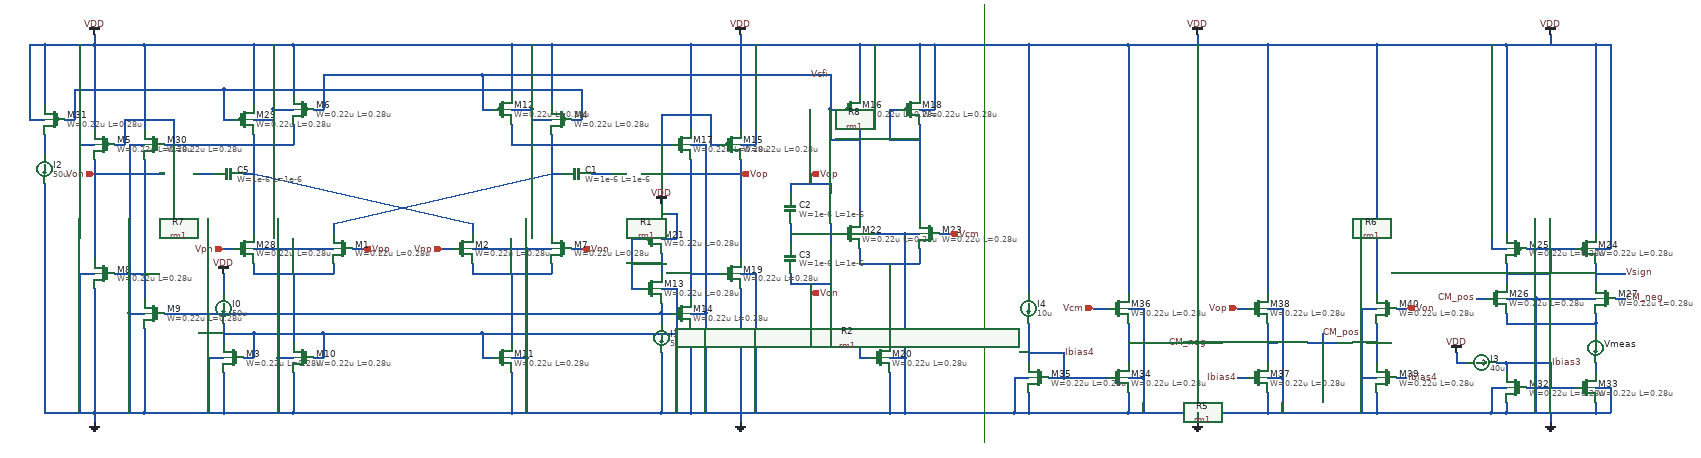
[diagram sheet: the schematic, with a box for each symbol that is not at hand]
v {xschem version=3.4.8RC file_version=1.3}
G {}
K {}
V {}
S {}
F {}
E {}
L 4 2250 -900 2250 -20 {}
N 780 -640 780 -440 {lab=#net1}
N 940 -380 940 -360 {lab=#net2}
N 780 -360 940 -360 {lab=#net2}
N 780 -380 780 -360 {lab=#net2}
N 1380 -640 1380 -440 {lab=#net3}
N 1220 -380 1220 -360 {lab=#net4}
N 1220 -360 1380 -360 {lab=#net4}
N 1380 -380 1380 -360 {lab=#net4}
N 360 -640 360 -600 {lab=#net5}
N 360 -820 360 -700 {lab=VDD}
N 360 -820 460 -820 {lab=VDD}
N 460 -820 560 -820 {lab=VDD}
N 360 -540 360 -80 {lab=GND}
N 460 -330 460 -80 {lab=GND}
N 360 -80 460 -80 {lab=GND}
N 560 -250 560 -80 {lab=GND}
N 460 -80 560 -80 {lab=GND}
N 720 -670 740 -670 {lab=#net6}
N 500 -360 560 -360 {lab=#net7}
N 560 -80 720 -80 {lab=GND}
N 720 -80 860 -80 {lab=GND}
N 860 -80 1300 -80 {lab=GND}
N 780 -820 780 -700 {lab=VDD}
N 560 -820 780 -820 {lab=VDD}
N 940 -460 940 -440 {lab=#net3}
N 1220 -460 1220 -440 {lab=#net1}
N 460 -590 460 -390 {lab=Von}
N 560 -590 560 -310 {lab=#net7}
N 460 -820 460 -650 {lab=VDD}
N 560 -820 560 -650 {lab=VDD}
N 600 -620 780 -620 {lab=#net1}
N 620 -670 620 -620 {lab=#net1}
N 520 -670 620 -670 {lab=#net1}
N 520 -670 520 -620 {lab=#net1}
N 500 -620 520 -620 {lab=#net1}
N 780 -620 860 -620 {lab=#net1}
N 860 -660 860 -620 {lab=#net1}
N 860 -820 860 -720 {lab=VDD}
N 780 -820 860 -820 {lab=VDD}
N 900 -690 920 -690 {lab=Vcfi}
N 1240 -690 1260 -690 {lab=Vcfi}
N 1300 -660 1300 -620 {lab=#net3}
N 1300 -620 1380 -620 {lab=#net3}
N 860 -820 1300 -820 {lab=VDD}
N 1300 -820 1300 -720 {lab=VDD}
N 1300 -820 1380 -820 {lab=VDD}
N 1380 -820 1380 -700 {lab=VDD}
N 1700 -620 1720 -620 {lab=#net3}
N 1700 -680 1700 -620 {lab=#net3}
N 1600 -680 1700 -680 {lab=#net3}
N 1600 -680 1600 -620 {lab=#net3}
N 1660 -820 1660 -650 {lab=VDD}
N 1760 -820 1760 -650 {lab=VDD}
N 1660 -820 1760 -820 {lab=VDD}
N 1660 -590 1660 -310 {lab=#net8}
N 1660 -250 1660 -80 {lab=GND}
N 1660 -360 1720 -360 {lab=#net8}
N 1760 -590 1760 -390 {lab=Vop}
N 1760 -330 1760 -80 {lab=GND}
N 1660 -80 1760 -80 {lab=GND}
N 1540 -330 1560 -330 {lab=#net9}
N 1540 -430 1540 -330 {lab=#net9}
N 1540 -430 1560 -430 {lab=#net9}
N 1600 -400 1600 -360 {lab=#net9}
N 1540 -380 1600 -380 {lab=#net9}
N 1600 -280 1600 -260 {lab=#net10}
N 1600 -300 1600 -280 {lab=#net10}
N 1600 -200 1600 -80 {lab=GND}
N 1300 -80 1600 -80 {lab=GND}
N 1600 -80 1660 -80 {lab=GND}
N 600 -280 1600 -280 {lab=#net10}
N 1600 -280 1620 -280 {lab=#net10}
N 1380 -620 1620 -620 {lab=#net3}
N 1380 -820 1660 -820 {lab=VDD}
N 1420 -410 1440 -410 {lab=Vnn}
N 1160 -410 1180 -410 {lab=Vnp}
N 980 -410 1000 -410 {lab=Vpp}
N 720 -410 740 -410 {lab=Vpn}
N 1940 -690 1960 -690 {lab=Vcfi}
N 1940 -690 1940 -630 {lab=Vcfi}
N 1940 -630 2000 -630 {lab=Vcfi}
N 2060 -690 2080 -690 {lab=#net11}
N 2060 -690 2060 -630 {lab=#net11}
N 2060 -630 2120 -630 {lab=#net11}
N 940 -460 1380 -560 {lab=#net3}
N 780 -560 1220 -460 {lab=#net1}
N 2000 -660 2000 -470 {lab=Vcfi}
N 2120 -660 2120 -470 {lab=#net11}
N 1940 -460 1940 -420 {lab=#net12}
N 1860 -460 1860 -420 {lab=#net12}
N 1860 -540 1860 -520 {lab=Vop}
N 1860 -540 1940 -540 {lab=Vop}
N 1940 -540 1940 -520 {lab=Vop}
N 1940 -360 1940 -340 {lab=Von}
N 1860 -340 1940 -340 {lab=Von}
N 1860 -360 1860 -340 {lab=Von}
N 1940 -440 1960 -440 {lab=#net12}
N 1860 -440 1940 -440 {lab=#net12}
N 1760 -820 2000 -820 {lab=VDD}
N 2000 -820 2000 -720 {lab=VDD}
N 2000 -820 2120 -820 {lab=VDD}
N 2120 -820 2120 -720 {lab=VDD}
N 2120 -410 2120 -380 {lab=#net13}
N 2000 -380 2120 -380 {lab=#net13}
N 2000 -410 2000 -380 {lab=#net13}
N 1760 -80 2060 -80 {lab=GND}
N 2160 -440 2180 -440 {lab=Vcm}
N 1900 -560 1900 -540 {lab=Vop}
N 1900 -340 1900 -320 {lab=Von}
N 720 -160 720 -80 {lab=GND}
N 1300 -160 1300 -80 {lab=GND}
N 2060 -160 2060 -80 {lab=GND}
N 2060 -380 2060 -220 {lab=#net13}
N 860 -360 860 -220 {lab=#net2}
N 1300 -360 1300 -220 {lab=#net4}
N 720 -240 780 -240 {lab=#net14}
N 780 -240 780 -190 {lab=#net14}
N 760 -190 780 -190 {lab=#net14}
N 900 -190 920 -190 {lab=#net14}
N 920 -240 920 -190 {lab=#net14}
N 780 -240 920 -240 {lab=#net14}
N 920 -240 1240 -240 {lab=#net14}
N 1240 -240 1240 -190 {lab=#net14}
N 1240 -190 1260 -190 {lab=#net14}
N 1240 -240 2000 -240 {lab=#net14}
N 2000 -240 2000 -190 {lab=#net14}
N 2000 -190 2020 -190 {lab=#net14}
N 400 -670 420 -670 {lab=#net6}
N 860 -160 860 -80 {lab=GND}
N 1420 -670 1440 -670 {lab=#net6}
N 820 -690 860 -690 {lab=VDD}
N 820 -690 820 -670 {lab=VDD}
N 780 -670 820 -670 {lab=VDD}
N 1300 -690 1340 -690 {lab=VDD}
N 1340 -690 1340 -670 {lab=VDD}
N 1340 -670 1380 -670 {lab=VDD}
N 2120 -690 2150 -690 {lab=VDD}
N 2000 -690 2030 -690 {lab=VDD}
N 1760 -620 1790 -620 {lab=VDD}
N 2060 -190 2090 -190 {lab=GND}
N 1660 -280 1690 -280 {lab=GND}
N 1600 -330 1630 -330 {lab=GND}
N 1760 -360 1790 -360 {lab=GND}
N 1660 -620 1690 -620 {lab=GND}
N 690 -190 720 -190 {lab=GND}
N 830 -190 860 -190 {lab=GND}
N 530 -280 560 -280 {lab=GND}
N 430 -360 460 -360 {lab=GND}
N 530 -620 560 -620 {lab=GND}
N 3340 -410 3440 -410 {lab=#net15}
N 3520 -310 3540 -310 {lab=CM_neg}
N 3240 -310 3260 -310 {lab=CM_pos}
N 3390 -410 3390 -360 {lab=#net15}
N 3300 -360 3390 -360 {lab=#net15}
N 3300 -280 3300 -260 {lab=#net16}
N 3300 -260 3480 -260 {lab=#net16}
N 3480 -280 3480 -260 {lab=#net16}
N 3340 -130 3440 -130 {lab=Ibias3}
N 3390 -180 3390 -130 {lab=Ibias3}
N 3300 -180 3390 -180 {lab=Ibias3}
N 3480 -100 3480 -80 {lab=GND}
N 3300 -80 3480 -80 {lab=GND}
N 3300 -100 3300 -80 {lab=GND}
N 3080 -290 3100 -290 {lab=Von}
N 2760 -290 2780 -290 {lab=Vop}
N 3480 -360 3540 -360 {lab=Vsign}
N 3040 -260 3040 -180 {lab=#net17}
N 2820 -260 2820 -180 {lab=#net18}
N 2820 -120 2820 -80 {lab=GND}
N 2820 -80 3040 -80 {lab=GND}
N 3040 -120 3040 -80 {lab=GND}
N 3010 -150 3040 -150 {lab=GND}
N 3010 -150 3010 -80 {lab=GND}
N 2850 -150 2850 -80 {lab=GND}
N 2820 -150 2850 -150 {lab=GND}
N 2380 -150 2410 -150 {lab=Ibias4}
N 2410 -200 2410 -150 {lab=Ibias4}
N 2340 -200 2410 -200 {lab=Ibias4}
N 2410 -150 2500 -150 {lab=Ibias4}
N 2540 -260 2540 -180 {lab=CM_neg}
N 2540 -80 2820 -80 {lab=GND}
N 2540 -120 2540 -80 {lab=GND}
N 2340 -80 2540 -80 {lab=GND}
N 2340 -120 2340 -80 {lab=GND}
N 2310 -150 2340 -150 {lab=GND}
N 2310 -150 2310 -80 {lab=GND}
N 2310 -80 2340 -80 {lab=GND}
N 2540 -150 2570 -150 {lab=GND}
N 2570 -150 2570 -80 {lab=GND}
N 2540 -290 2570 -290 {lab=GND}
N 2570 -290 2570 -150 {lab=GND}
N 2820 -290 2850 -290 {lab=GND}
N 2850 -290 2850 -150 {lab=GND}
N 3010 -290 3040 -290 {lab=GND}
N 3010 -290 3010 -150 {lab=GND}
N 2470 -290 2500 -290 {lab=Vcm}
N 2540 -220 2620 -220 {lab=CM_neg}
N 2900 -220 2960 -220 {lab=CM_pos}
N 2820 -220 2840 -220 {lab=#net18}
N 3020 -220 3040 -220 {lab=#net17}
N 2930 -240 2930 -220 {lab=CM_pos}
N 2760 -150 2780 -150 {lab=Ibias4}
N 3080 -150 3100 -150 {lab=Ibias4}
N 1940 -760 1940 -690 {lab=Vcfi}
N 1240 -760 1940 -760 {lab=Vcfi}
N 1240 -760 1240 -690 {lab=Vcfi}
N 920 -760 1240 -760 {lab=Vcfi}
N 920 -760 920 -690 {lab=Vcfi}
N 1440 -730 1440 -670 {lab=#net6}
N 720 -730 1440 -730 {lab=#net6}
N 720 -730 720 -670 {lab=#net6}
N 420 -730 720 -730 {lab=#net6}
N 420 -730 420 -670 {lab=#net6}
N 820 -820 820 -690 {lab=VDD}
N 1340 -820 1340 -690 {lab=VDD}
N 3300 -380 3300 -340 {lab=#net15}
N 3480 -380 3480 -340 {lab=Vsign}
N 3280 -180 3300 -180 {lab=Ibias3}
N 3200 -180 3220 -180 {lab=VDD}
N 3200 -200 3200 -180 {lab=VDD}
N 3300 -180 3300 -160 {lab=Ibias3}
N 3480 -180 3480 -160 {lab=#net19}
N 3480 -260 3480 -240 {lab=#net16}
N 3270 -410 3300 -410 {lab=VDD}
N 3480 -410 3510 -410 {lab=VDD}
N 3480 -130 3510 -130 {lab=GND}
N 3510 -130 3510 -80 {lab=GND}
N 3480 -80 3510 -80 {lab=GND}
N 3270 -80 3300 -80 {lab=GND}
N 3270 -130 3270 -80 {lab=GND}
N 3270 -130 3300 -130 {lab=GND}
N 2090 -190 2090 -80 {lab=GND}
N 2060 -80 2090 -80 {lab=GND}
N 1690 -280 1690 -80 {lab=GND}
N 1300 -190 1330 -190 {lab=GND}
N 1330 -190 1330 -80 {lab=GND}
N 830 -190 830 -80 {lab=GND}
N 690 -190 690 -80 {lab=GND}
N 530 -280 530 -80 {lab=GND}
N 430 -360 430 -80 {lab=GND}
N 760 -560 780 -560 {lab=#net1}
N 660 -560 700 -560 {lab=#net20}
N 460 -560 600 -560 {lab=Von}
N 1380 -560 1400 -560 {lab=#net3}
N 1460 -560 1500 -560 {lab=#net21}
N 1560 -560 1760 -560 {lab=Vop}
N 2150 -820 2150 -690 {lab=VDD}
N 2120 -820 2150 -820 {lab=VDD}
N 2030 -820 2030 -690 {lab=VDD}
N 1790 -820 1790 -620 {lab=VDD}
N 430 -620 460 -620 {lab=VDD}
N 430 -820 430 -620 {lab=VDD}
N 330 -670 360 -670 {lab=VDD}
N 330 -820 330 -670 {lab=VDD}
N 330 -820 360 -820 {lab=VDD}
N 2090 -440 2090 -190 {lab=GND}
N 2090 -440 2120 -440 {lab=GND}
N 2000 -440 2090 -440 {lab=GND}
N 1690 -620 1690 -280 {lab=GND}
N 1790 -360 1790 -80 {lab=GND}
N 1330 -410 1330 -190 {lab=GND}
N 1330 -410 1380 -410 {lab=GND}
N 1220 -410 1330 -410 {lab=GND}
N 830 -410 830 -190 {lab=GND}
N 780 -410 830 -410 {lab=GND}
N 830 -410 940 -410 {lab=GND}
N 3360 -310 3360 -80 {lab=GND}
N 3300 -310 3360 -310 {lab=GND}
N 3360 -310 3480 -310 {lab=GND}
N 720 -360 720 -320 {lab=VDD}
N 720 -260 720 -220 {lab=#net14}
N 1600 -500 1600 -460 {lab=VDD}
N 1600 -430 1630 -430 {lab=VDD}
N 1630 -480 1630 -430 {lab=VDD}
N 1600 -480 1630 -480 {lab=VDD}
N 1630 -330 1630 -80 {lab=GND}
N 2340 -260 2340 -180 {lab=Ibias4}
N 460 -80 460 -60 {lab=GND}
N 1760 -80 1760 -60 {lab=GND}
N 2680 -80 2680 -60 {lab=GND}
N 3390 -80 3390 -60 {lab=GND}
N 460 -840 460 -820 {lab=VDD}
N 1760 -840 1760 -820 {lab=VDD}
N 3040 -80 3270 -80 {lab=GND}
N 2340 -820 2340 -320 {lab=VDD}
N 2540 -820 2540 -320 {lab=VDD}
N 2340 -820 2540 -820 {lab=VDD}
N 2820 -820 2820 -320 {lab=VDD}
N 2540 -820 2820 -820 {lab=VDD}
N 3040 -820 3040 -320 {lab=VDD}
N 2820 -820 3040 -820 {lab=VDD}
N 3300 -820 3300 -440 {lab=VDD}
N 3040 -820 3300 -820 {lab=VDD}
N 3480 -820 3480 -440 {lab=VDD}
N 3300 -820 3480 -820 {lab=VDD}
N 3270 -820 3270 -410 {lab=VDD}
N 3510 -820 3510 -410 {lab=VDD}
N 3480 -820 3510 -820 {lab=VDD}
N 2680 -840 2680 -820 {lab=VDD}
N 3390 -840 3390 -820 {lab=VDD}
N 2150 -820 2340 -820 {lab=VDD}
N 2090 -80 2310 -80 {lab=GND}
N 530 -620 530 -280 {lab=GND}
C {ipin.sym} 720 -410 0 0 {name=p1 lab=Vpn}
C {ipin.sym} 1000 -410 0 1 {name=p2 lab=Vpp}
C {ipin.sym} 1160 -410 0 0 {name=p3 lab=Vnp}
C {ipin.sym} 1440 -410 0 1 {name=p4 lab=Vnn}
C {isource.sym} 720 -290 0 0 {name=I0 value=50u}
C {isource.sym} 1600 -230 0 0 {name=I1 value=50u}
C {isource.sym} 360 -570 0 0 {name=I2 value=50u}
C {opin.sym} 1900 -320 0 0 {name=p12 lab=Von}
C {opin.sym} 1900 -560 0 0 {name=p10 lab=Vop}
C {opin.sym} 1760 -560 0 0 {name=p11 lab=Vop}
C {opin.sym} 460 -560 0 1 {name=p13 lab=Von}
C {lab_wire.sym} 1940 -760 0 0 {name=p14 sig_type=std_logic lab=Vcfi}
C {symbols/nfet_03v3.sym} 760 -410 0 0 {name=M28
L=0.28u
W=0.22u
nf=1
m=1
ad="'int((nf+1)/2) * W/nf * 0.18u'"
pd="'2*int((nf+1)/2) * (W/nf + 0.18u)'"
as="'int((nf+2)/2) * W/nf * 0.18u'"
ps="'2*int((nf+2)/2) * (W/nf + 0.18u)'"
nrd="'0.18u / W'" nrs="'0.18u / W'"
sa=0 sb=0 sd=0
model=nfet_03v3
spiceprefix=X
}
C {symbols/pfet_03v3.sym} 760 -670 0 0 {name=M29
L=0.28u
W=0.22u
nf=1
m=1
ad="'int((nf+1)/2) * W/nf * 0.18u'"
pd="'2*int((nf+1)/2) * (W/nf + 0.18u)'"
as="'int((nf+2)/2) * W/nf * 0.18u'"
ps="'2*int((nf+2)/2) * (W/nf + 0.18u)'"
nrd="'0.18u / W'" nrs="'0.18u / W'"
sa=0 sb=0 sd=0
model=pfet_03v3
spiceprefix=X
}
C {gnd.sym} 460 -60 0 0 {name=l1 lab=GND}
C {vdd.sym} 460 -840 0 0 {name=l2 lab=VDD}
C {symbols/nfet_03v3.sym} 580 -620 0 1 {name=M30
L=0.28u
W=0.22u
nf=1
m=1
ad="'int((nf+1)/2) * W/nf * 0.18u'"
pd="'2*int((nf+1)/2) * (W/nf + 0.18u)'"
as="'int((nf+2)/2) * W/nf * 0.18u'"
ps="'2*int((nf+2)/2) * (W/nf + 0.18u)'"
nrd="'0.18u / W'" nrs="'0.18u / W'"
sa=0 sb=0 sd=0
model=nfet_03v3
spiceprefix=X
}
C {symbols/pfet_03v3.sym} 380 -670 0 1 {name=M31
L=0.28u
W=0.22u
nf=1
m=1
ad="'int((nf+1)/2) * W/nf * 0.18u'"
pd="'2*int((nf+1)/2) * (W/nf + 0.18u)'"
as="'int((nf+2)/2) * W/nf * 0.18u'"
ps="'2*int((nf+2)/2) * (W/nf + 0.18u)'"
nrd="'0.18u / W'" nrs="'0.18u / W'"
sa=0 sb=0 sd=0
model=pfet_03v3
spiceprefix=X
}
C {symbols/pfet_03v3.sym} 480 -620 0 1 {name=M5
L=0.28u
W=0.22u
nf=1
m=1
ad="'int((nf+1)/2) * W/nf * 0.18u'"
pd="'2*int((nf+1)/2) * (W/nf + 0.18u)'"
as="'int((nf+2)/2) * W/nf * 0.18u'"
ps="'2*int((nf+2)/2) * (W/nf + 0.18u)'"
nrd="'0.18u / W'" nrs="'0.18u / W'"
sa=0 sb=0 sd=0
model=pfet_03v3
spiceprefix=X
}
C {symbols/pfet_03v3.sym} 880 -690 0 1 {name=M6
L=0.28u
W=0.22u
nf=1
m=1
ad="'int((nf+1)/2) * W/nf * 0.18u'"
pd="'2*int((nf+1)/2) * (W/nf + 0.18u)'"
as="'int((nf+2)/2) * W/nf * 0.18u'"
ps="'2*int((nf+2)/2) * (W/nf + 0.18u)'"
nrd="'0.18u / W'" nrs="'0.18u / W'"
sa=0 sb=0 sd=0
model=pfet_03v3
spiceprefix=X
}
C {symbols/pfet_03v3.sym} 1400 -670 0 1 {name=M4
L=0.28u
W=0.22u
nf=1
m=1
ad="'int((nf+1)/2) * W/nf * 0.18u'"
pd="'2*int((nf+1)/2) * (W/nf + 0.18u)'"
as="'int((nf+2)/2) * W/nf * 0.18u'"
ps="'2*int((nf+2)/2) * (W/nf + 0.18u)'"
nrd="'0.18u / W'" nrs="'0.18u / W'"
sa=0 sb=0 sd=0
model=pfet_03v3
spiceprefix=X
}
C {symbols/pfet_03v3.sym} 1280 -690 0 0 {name=M12
L=0.28u
W=0.22u
nf=1
m=1
ad="'int((nf+1)/2) * W/nf * 0.18u'"
pd="'2*int((nf+1)/2) * (W/nf + 0.18u)'"
as="'int((nf+2)/2) * W/nf * 0.18u'"
ps="'2*int((nf+2)/2) * (W/nf + 0.18u)'"
nrd="'0.18u / W'" nrs="'0.18u / W'"
sa=0 sb=0 sd=0
model=pfet_03v3
spiceprefix=X
}
C {symbols/pfet_03v3.sym} 1740 -620 0 0 {name=M15
L=0.28u
W=0.22u
nf=1
m=1
ad="'int((nf+1)/2) * W/nf * 0.18u'"
pd="'2*int((nf+1)/2) * (W/nf + 0.18u)'"
as="'int((nf+2)/2) * W/nf * 0.18u'"
ps="'2*int((nf+2)/2) * (W/nf + 0.18u)'"
nrd="'0.18u / W'" nrs="'0.18u / W'"
sa=0 sb=0 sd=0
model=pfet_03v3
spiceprefix=X
}
C {symbols/pfet_03v3.sym} 1980 -690 0 0 {name=M16
L=0.28u
W=0.22u
nf=1
m=1
ad="'int((nf+1)/2) * W/nf * 0.18u'"
pd="'2*int((nf+1)/2) * (W/nf + 0.18u)'"
as="'int((nf+2)/2) * W/nf * 0.18u'"
ps="'2*int((nf+2)/2) * (W/nf + 0.18u)'"
nrd="'0.18u / W'" nrs="'0.18u / W'"
sa=0 sb=0 sd=0
model=pfet_03v3
spiceprefix=X
}
C {symbols/pfet_03v3.sym} 2100 -690 0 0 {name=M18
L=0.28u
W=0.22u
nf=1
m=1
ad="'int((nf+1)/2) * W/nf * 0.18u'"
pd="'2*int((nf+1)/2) * (W/nf + 0.18u)'"
as="'int((nf+2)/2) * W/nf * 0.18u'"
ps="'2*int((nf+2)/2) * (W/nf + 0.18u)'"
nrd="'0.18u / W'" nrs="'0.18u / W'"
sa=0 sb=0 sd=0
model=pfet_03v3
spiceprefix=X
}
C {symbols/pfet_03v3.sym} 1580 -430 0 0 {name=M21
L=0.28u
W=0.22u
nf=1
m=1
ad="'int((nf+1)/2) * W/nf * 0.18u'"
pd="'2*int((nf+1)/2) * (W/nf + 0.18u)'"
as="'int((nf+2)/2) * W/nf * 0.18u'"
ps="'2*int((nf+2)/2) * (W/nf + 0.18u)'"
nrd="'0.18u / W'" nrs="'0.18u / W'"
sa=0 sb=0 sd=0
model=pfet_03v3
spiceprefix=X
}
C {symbols/nfet_03v3.sym} 960 -410 0 1 {name=M1
L=0.28u
W=0.22u
nf=1
m=1
ad="'int((nf+1)/2) * W/nf * 0.18u'"
pd="'2*int((nf+1)/2) * (W/nf + 0.18u)'"
as="'int((nf+2)/2) * W/nf * 0.18u'"
ps="'2*int((nf+2)/2) * (W/nf + 0.18u)'"
nrd="'0.18u / W'" nrs="'0.18u / W'"
sa=0 sb=0 sd=0
model=nfet_03v3
spiceprefix=X
}
C {symbols/nfet_03v3.sym} 1200 -410 0 0 {name=M2
L=0.28u
W=0.22u
nf=1
m=1
ad="'int((nf+1)/2) * W/nf * 0.18u'"
pd="'2*int((nf+1)/2) * (W/nf + 0.18u)'"
as="'int((nf+2)/2) * W/nf * 0.18u'"
ps="'2*int((nf+2)/2) * (W/nf + 0.18u)'"
nrd="'0.18u / W'" nrs="'0.18u / W'"
sa=0 sb=0 sd=0
model=nfet_03v3
spiceprefix=X
}
C {symbols/nfet_03v3.sym} 1400 -410 0 1 {name=M7
L=0.28u
W=0.22u
nf=1
m=1
ad="'int((nf+1)/2) * W/nf * 0.18u'"
pd="'2*int((nf+1)/2) * (W/nf + 0.18u)'"
as="'int((nf+2)/2) * W/nf * 0.18u'"
ps="'2*int((nf+2)/2) * (W/nf + 0.18u)'"
nrd="'0.18u / W'" nrs="'0.18u / W'"
sa=0 sb=0 sd=0
model=nfet_03v3
spiceprefix=X
}
C {symbols/nfet_03v3.sym} 740 -190 0 1 {name=M3
L=0.28u
W=0.22u
nf=1
m=1
ad="'int((nf+1)/2) * W/nf * 0.18u'"
pd="'2*int((nf+1)/2) * (W/nf + 0.18u)'"
as="'int((nf+2)/2) * W/nf * 0.18u'"
ps="'2*int((nf+2)/2) * (W/nf + 0.18u)'"
nrd="'0.18u / W'" nrs="'0.18u / W'"
sa=0 sb=0 sd=0
model=nfet_03v3
spiceprefix=X
}
C {symbols/nfet_03v3.sym} 880 -190 0 1 {name=M10
L=0.28u
W=0.22u
nf=1
m=1
ad="'int((nf+1)/2) * W/nf * 0.18u'"
pd="'2*int((nf+1)/2) * (W/nf + 0.18u)'"
as="'int((nf+2)/2) * W/nf * 0.18u'"
ps="'2*int((nf+2)/2) * (W/nf + 0.18u)'"
nrd="'0.18u / W'" nrs="'0.18u / W'"
sa=0 sb=0 sd=0
model=nfet_03v3
spiceprefix=X
}
C {symbols/nfet_03v3.sym} 1280 -190 0 0 {name=M11
L=0.28u
W=0.22u
nf=1
m=1
ad="'int((nf+1)/2) * W/nf * 0.18u'"
pd="'2*int((nf+1)/2) * (W/nf + 0.18u)'"
as="'int((nf+2)/2) * W/nf * 0.18u'"
ps="'2*int((nf+2)/2) * (W/nf + 0.18u)'"
nrd="'0.18u / W'" nrs="'0.18u / W'"
sa=0 sb=0 sd=0
model=nfet_03v3
spiceprefix=X
}
C {symbols/nfet_03v3.sym} 1580 -330 0 0 {name=M13
L=0.28u
W=0.22u
nf=1
m=1
ad="'int((nf+1)/2) * W/nf * 0.18u'"
pd="'2*int((nf+1)/2) * (W/nf + 0.18u)'"
as="'int((nf+2)/2) * W/nf * 0.18u'"
ps="'2*int((nf+2)/2) * (W/nf + 0.18u)'"
nrd="'0.18u / W'" nrs="'0.18u / W'"
sa=0 sb=0 sd=0
model=nfet_03v3
spiceprefix=X
}
C {symbols/nfet_03v3.sym} 1640 -280 0 0 {name=M14
L=0.28u
W=0.22u
nf=1
m=1
ad="'int((nf+1)/2) * W/nf * 0.18u'"
pd="'2*int((nf+1)/2) * (W/nf + 0.18u)'"
as="'int((nf+2)/2) * W/nf * 0.18u'"
ps="'2*int((nf+2)/2) * (W/nf + 0.18u)'"
nrd="'0.18u / W'" nrs="'0.18u / W'"
sa=0 sb=0 sd=0
model=nfet_03v3
spiceprefix=X
}
C {symbols/nfet_03v3.sym} 1740 -360 0 0 {name=M19
L=0.28u
W=0.22u
nf=1
m=1
ad="'int((nf+1)/2) * W/nf * 0.18u'"
pd="'2*int((nf+1)/2) * (W/nf + 0.18u)'"
as="'int((nf+2)/2) * W/nf * 0.18u'"
ps="'2*int((nf+2)/2) * (W/nf + 0.18u)'"
nrd="'0.18u / W'" nrs="'0.18u / W'"
sa=0 sb=0 sd=0
model=nfet_03v3
spiceprefix=X
}
C {symbols/nfet_03v3.sym} 2040 -190 0 0 {name=M20
L=0.28u
W=0.22u
nf=1
m=1
ad="'int((nf+1)/2) * W/nf * 0.18u'"
pd="'2*int((nf+1)/2) * (W/nf + 0.18u)'"
as="'int((nf+2)/2) * W/nf * 0.18u'"
ps="'2*int((nf+2)/2) * (W/nf + 0.18u)'"
nrd="'0.18u / W'" nrs="'0.18u / W'"
sa=0 sb=0 sd=0
model=nfet_03v3
spiceprefix=X
}
C {symbols/nfet_03v3.sym} 1980 -440 0 0 {name=M22
L=0.28u
W=0.22u
nf=1
m=1
ad="'int((nf+1)/2) * W/nf * 0.18u'"
pd="'2*int((nf+1)/2) * (W/nf + 0.18u)'"
as="'int((nf+2)/2) * W/nf * 0.18u'"
ps="'2*int((nf+2)/2) * (W/nf + 0.18u)'"
nrd="'0.18u / W'" nrs="'0.18u / W'"
sa=0 sb=0 sd=0
model=nfet_03v3
spiceprefix=X
}
C {symbols/nfet_03v3.sym} 1640 -620 0 0 {name=M17
L=0.28u
W=0.22u
nf=1
m=1
ad="'int((nf+1)/2) * W/nf * 0.18u'"
pd="'2*int((nf+1)/2) * (W/nf + 0.18u)'"
as="'int((nf+2)/2) * W/nf * 0.18u'"
ps="'2*int((nf+2)/2) * (W/nf + 0.18u)'"
nrd="'0.18u / W'" nrs="'0.18u / W'"
sa=0 sb=0 sd=0
model=nfet_03v3
spiceprefix=X
}
C {symbols/nfet_03v3.sym} 480 -360 0 1 {name=M8
L=0.28u
W=0.22u
nf=1
m=1
ad="'int((nf+1)/2) * W/nf * 0.18u'"
pd="'2*int((nf+1)/2) * (W/nf + 0.18u)'"
as="'int((nf+2)/2) * W/nf * 0.18u'"
ps="'2*int((nf+2)/2) * (W/nf + 0.18u)'"
nrd="'0.18u / W'" nrs="'0.18u / W'"
sa=0 sb=0 sd=0
model=nfet_03v3
spiceprefix=X
}
C {symbols/nfet_03v3.sym} 580 -280 0 1 {name=M9
L=0.28u
W=0.22u
nf=1
m=1
ad="'int((nf+1)/2) * W/nf * 0.18u'"
pd="'2*int((nf+1)/2) * (W/nf + 0.18u)'"
as="'int((nf+2)/2) * W/nf * 0.18u'"
ps="'2*int((nf+2)/2) * (W/nf + 0.18u)'"
nrd="'0.18u / W'" nrs="'0.18u / W'"
sa=0 sb=0 sd=0
model=nfet_03v3
spiceprefix=X
}
C {symbols/nfet_03v3.sym} 2140 -440 0 1 {name=M23
L=0.28u
W=0.22u
nf=1
m=1
ad="'int((nf+1)/2) * W/nf * 0.18u'"
pd="'2*int((nf+1)/2) * (W/nf + 0.18u)'"
as="'int((nf+2)/2) * W/nf * 0.18u'"
ps="'2*int((nf+2)/2) * (W/nf + 0.18u)'"
nrd="'0.18u / W'" nrs="'0.18u / W'"
sa=0 sb=0 sd=0
model=nfet_03v3
spiceprefix=X
}
C {gnd.sym} 1760 -60 0 0 {name=l11 lab=GND}
C {vdd.sym} 1760 -840 0 0 {name=l12 lab=VDD}
C {symbols/pfet_03v3.sym} 3460 -410 0 0 {name=M24
L=0.28u
W=0.22u
nf=1
m=1
ad="'int((nf+1)/2) * W/nf * 0.18u'"
pd="'2*int((nf+1)/2) * (W/nf + 0.18u)'"
as="'int((nf+2)/2) * W/nf * 0.18u'"
ps="'2*int((nf+2)/2) * (W/nf + 0.18u)'"
nrd="'0.18u / W'" nrs="'0.18u / W'"
sa=0 sb=0 sd=0
model=pfet_03v3
spiceprefix=X
}
C {symbols/pfet_03v3.sym} 3320 -410 0 1 {name=M25
L=0.28u
W=0.22u
nf=1
m=1
ad="'int((nf+1)/2) * W/nf * 0.18u'"
pd="'2*int((nf+1)/2) * (W/nf + 0.18u)'"
as="'int((nf+2)/2) * W/nf * 0.18u'"
ps="'2*int((nf+2)/2) * (W/nf + 0.18u)'"
nrd="'0.18u / W'" nrs="'0.18u / W'"
sa=0 sb=0 sd=0
model=pfet_03v3
spiceprefix=X
}
C {symbols/nfet_03v3.sym} 3280 -310 0 0 {name=M26
L=0.28u
W=0.22u
nf=1
m=1
ad="'int((nf+1)/2) * W/nf * 0.18u'"
pd="'2*int((nf+1)/2) * (W/nf + 0.18u)'"
as="'int((nf+2)/2) * W/nf * 0.18u'"
ps="'2*int((nf+2)/2) * (W/nf + 0.18u)'"
nrd="'0.18u / W'" nrs="'0.18u / W'"
sa=0 sb=0 sd=0
model=nfet_03v3
spiceprefix=X
}
C {symbols/nfet_03v3.sym} 3500 -310 0 1 {name=M27
L=0.28u
W=0.22u
nf=1
m=1
ad="'int((nf+1)/2) * W/nf * 0.18u'"
pd="'2*int((nf+1)/2) * (W/nf + 0.18u)'"
as="'int((nf+2)/2) * W/nf * 0.18u'"
ps="'2*int((nf+2)/2) * (W/nf + 0.18u)'"
nrd="'0.18u / W'" nrs="'0.18u / W'"
sa=0 sb=0 sd=0
model=nfet_03v3
spiceprefix=X
}
C {vdd.sym} 3390 -840 0 0 {name=l31 lab=VDD}
C {ammeter.sym} 3480 -210 0 0 {name=Vmeas savecurrent=true spice_ignore=0}
C {symbols/nfet_03v3.sym} 3320 -130 0 1 {name=M32
L=0.28u
W=0.22u
nf=1
m=1
ad="'int((nf+1)/2) * W/nf * 0.18u'"
pd="'2*int((nf+1)/2) * (W/nf + 0.18u)'"
as="'int((nf+2)/2) * W/nf * 0.18u'"
ps="'2*int((nf+2)/2) * (W/nf + 0.18u)'"
nrd="'0.18u / W'" nrs="'0.18u / W'"
sa=0 sb=0 sd=0
model=nfet_03v3
spiceprefix=X
}
C {symbols/nfet_03v3.sym} 3460 -130 0 0 {name=M33
L=0.28u
W=0.22u
nf=1
m=1
ad="'int((nf+1)/2) * W/nf * 0.18u'"
pd="'2*int((nf+1)/2) * (W/nf + 0.18u)'"
as="'int((nf+2)/2) * W/nf * 0.18u'"
ps="'2*int((nf+2)/2) * (W/nf + 0.18u)'"
nrd="'0.18u / W'" nrs="'0.18u / W'"
sa=0 sb=0 sd=0
model=nfet_03v3
spiceprefix=X
}
C {isource.sym} 3250 -180 3 0 {name=I3 value=40u}
C {vdd.sym} 3200 -200 0 0 {name=l32 lab=VDD}
C {gnd.sym} 3390 -60 0 0 {name=l33 lab=GND}
C {lab_wire.sym} 3540 -360 0 1 {name=p15 sig_type=std_logic lab=Vsign}
C {lab_wire.sym} 3390 -180 0 1 {name=p16 sig_type=std_logic lab=Ibias3}
C {lab_wire.sym} 3540 -310 0 1 {name=p5 sig_type=std_logic lab=CM_neg}
C {lab_wire.sym} 3240 -310 0 0 {name=p6 sig_type=std_logic lab=CM_pos}
C {symbols/nfet_03v3.sym} 2520 -150 0 0 {name=M34
L=0.28u
W=0.22u
nf=1
m=1
ad="'int((nf+1)/2) * W/nf * 0.18u'"
pd="'2*int((nf+1)/2) * (W/nf + 0.18u)'"
as="'int((nf+2)/2) * W/nf * 0.18u'"
ps="'2*int((nf+2)/2) * (W/nf + 0.18u)'"
nrd="'0.18u / W'" nrs="'0.18u / W'"
sa=0 sb=0 sd=0
model=nfet_03v3
spiceprefix=X
}
C {symbols/nfet_03v3.sym} 2360 -150 0 1 {name=M35
L=0.28u
W=0.22u
nf=1
m=1
ad="'int((nf+1)/2) * W/nf * 0.18u'"
pd="'2*int((nf+1)/2) * (W/nf + 0.18u)'"
as="'int((nf+2)/2) * W/nf * 0.18u'"
ps="'2*int((nf+2)/2) * (W/nf + 0.18u)'"
nrd="'0.18u / W'" nrs="'0.18u / W'"
sa=0 sb=0 sd=0
model=nfet_03v3
spiceprefix=X
}
C {symbols/nfet_03v3.sym} 2520 -290 0 0 {name=M36
L=0.28u
W=0.22u
nf=1
m=1
ad="'int((nf+1)/2) * W/nf * 0.18u'"
pd="'2*int((nf+1)/2) * (W/nf + 0.18u)'"
as="'int((nf+2)/2) * W/nf * 0.18u'"
ps="'2*int((nf+2)/2) * (W/nf + 0.18u)'"
nrd="'0.18u / W'" nrs="'0.18u / W'"
sa=0 sb=0 sd=0
model=nfet_03v3
spiceprefix=X
}
C {symbols/nfet_03v3.sym} 2800 -150 0 0 {name=M37
L=0.28u
W=0.22u
nf=1
m=1
ad="'int((nf+1)/2) * W/nf * 0.18u'"
pd="'2*int((nf+1)/2) * (W/nf + 0.18u)'"
as="'int((nf+2)/2) * W/nf * 0.18u'"
ps="'2*int((nf+2)/2) * (W/nf + 0.18u)'"
nrd="'0.18u / W'" nrs="'0.18u / W'"
sa=0 sb=0 sd=0
model=nfet_03v3
spiceprefix=X
}
C {symbols/nfet_03v3.sym} 2800 -290 0 0 {name=M38
L=0.28u
W=0.22u
nf=1
m=1
ad="'int((nf+1)/2) * W/nf * 0.18u'"
pd="'2*int((nf+1)/2) * (W/nf + 0.18u)'"
as="'int((nf+2)/2) * W/nf * 0.18u'"
ps="'2*int((nf+2)/2) * (W/nf + 0.18u)'"
nrd="'0.18u / W'" nrs="'0.18u / W'"
sa=0 sb=0 sd=0
model=nfet_03v3
spiceprefix=X
}
C {symbols/nfet_03v3.sym} 3060 -150 0 1 {name=M39
L=0.28u
W=0.22u
nf=1
m=1
ad="'int((nf+1)/2) * W/nf * 0.18u'"
pd="'2*int((nf+1)/2) * (W/nf + 0.18u)'"
as="'int((nf+2)/2) * W/nf * 0.18u'"
ps="'2*int((nf+2)/2) * (W/nf + 0.18u)'"
nrd="'0.18u / W'" nrs="'0.18u / W'"
sa=0 sb=0 sd=0
model=nfet_03v3
spiceprefix=X
}
C {symbols/nfet_03v3.sym} 3060 -290 0 1 {name=M40
L=0.28u
W=0.22u
nf=1
m=1
ad="'int((nf+1)/2) * W/nf * 0.18u'"
pd="'2*int((nf+1)/2) * (W/nf + 0.18u)'"
as="'int((nf+2)/2) * W/nf * 0.18u'"
ps="'2*int((nf+2)/2) * (W/nf + 0.18u)'"
nrd="'0.18u / W'" nrs="'0.18u / W'"
sa=0 sb=0 sd=0
model=nfet_03v3
spiceprefix=X
}
C {opin.sym} 2760 -290 0 1 {name=p17 lab=Vop}
C {opin.sym} 3100 -290 0 0 {name=p18 lab=Von}
C {gnd.sym} 2680 -60 0 0 {name=l34 lab=GND}
C {isource.sym} 2340 -290 0 0 {name=I4 value=10u}
C {ipin.sym} 2180 -440 0 1 {name=p20 lab=Vcm}
C {ipin.sym} 2470 -290 0 0 {name=p21 lab=Vcm}
C {vdd.sym} 2680 -840 0 0 {name=l35 lab=VDD}
C {lab_wire.sym} 2930 -240 0 1 {name=p9 sig_type=std_logic lab=CM_pos}
C {lab_wire.sym} 2620 -220 0 1 {name=p19 sig_type=std_logic lab=CM_neg}
C {symbols/rm1.sym} 2870 -220 1 0 {name=R5
W=0.6e-6
L=0.6e-6
model=rm1
spiceprefix=X
m=1}
C {symbols/rm1.sym} 2990 -220 1 0 {name=R6
W=0.6e-6
L=0.6e-6
model=rm1
spiceprefix=X
m=1}
C {lab_wire.sym} 2410 -200 0 1 {name=p22 sig_type=std_logic lab=Ibias4}
C {lab_wire.sym} 3100 -150 0 1 {name=p23 sig_type=std_logic lab=Ibias4}
C {lab_wire.sym} 2760 -150 0 0 {name=p24 sig_type=std_logic lab=Ibias4}
C {symbols/rm1.sym} 630 -560 3 0 {name=R7
W=0.6e-6
L=0.6e-6
model=rm1
spiceprefix=X
m=1}
C {symbols/cap_mim_2f0fF.sym} 730 -560 3 0 {name=C5
W=1e-6
L=1e-6
model=cap_mim_2f0fF
spiceprefix=X
m=1}
C {symbols/rm1.sym} 1530 -560 1 1 {name=R1
W=0.6e-6
L=0.6e-6
model=rm1
spiceprefix=X
m=1}
C {symbols/cap_mim_2f0fF.sym} 1430 -560 1 1 {name=C1
W=1e-6
L=1e-6
model=cap_mim_2f0fF
spiceprefix=X
m=1}
C {vdd.sym} 720 -360 0 0 {name=l3 lab=VDD}
C {vdd.sym} 1600 -500 0 0 {name=l4 lab=VDD}
C {symbols/cap_mim_2f0fF.sym} 1860 -490 0 1 {name=C2
W=1e-6
L=1e-6
model=cap_mim_2f0fF
spiceprefix=X
m=1}
C {symbols/rm1.sym} 1940 -490 2 1 {name=R8
W=0.6e-6
L=0.6e-6
model=rm1
spiceprefix=X
m=1}
C {symbols/cap_mim_2f0fF.sym} 1860 -390 0 1 {name=C3
W=1e-6
L=1e-6
model=cap_mim_2f0fF
spiceprefix=X
m=1}
C {symbols/rm1.sym} 1940 -390 2 1 {name=R2
W=0.6e-6
L=0.6e-6
model=rm1
spiceprefix=X
m=1}
